VERSION 5.7 ;
  NOWIREEXTENSIONATPIN ON ;
  DIVIDERCHAR "/" ;
  BUSBITCHARS "[]" ;
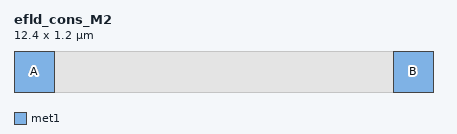
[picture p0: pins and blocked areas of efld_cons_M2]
MACRO efld_cons_M2
  CLASS BLOCK ;
  FOREIGN efld_cons_M2 ;
  ORIGIN 0.000 0.000 ;
  SIZE 12.400 BY 1.200 ;
  PIN A
    DIRECTION INOUT ;
    USE SIGNAL ;
    PORT
      LAYER met1 ;
        RECT 0.000 0.000 1.200 1.200 ;
    END
  END A
  PIN B
    DIRECTION INOUT ;
    USE SIGNAL ;
    PORT
      LAYER met1 ;
        RECT 11.200 0.000 12.400 1.200 ;
    END
  END B
  OBS
    LAYER met1 ;
      RECT 1.200 0.000 11.200 1.200 ;
    LAYER li1 ;
      RECT 0.000 0.000 12.400 1.200 ;
  END
END efld_cons_M2
END LIBRARY
